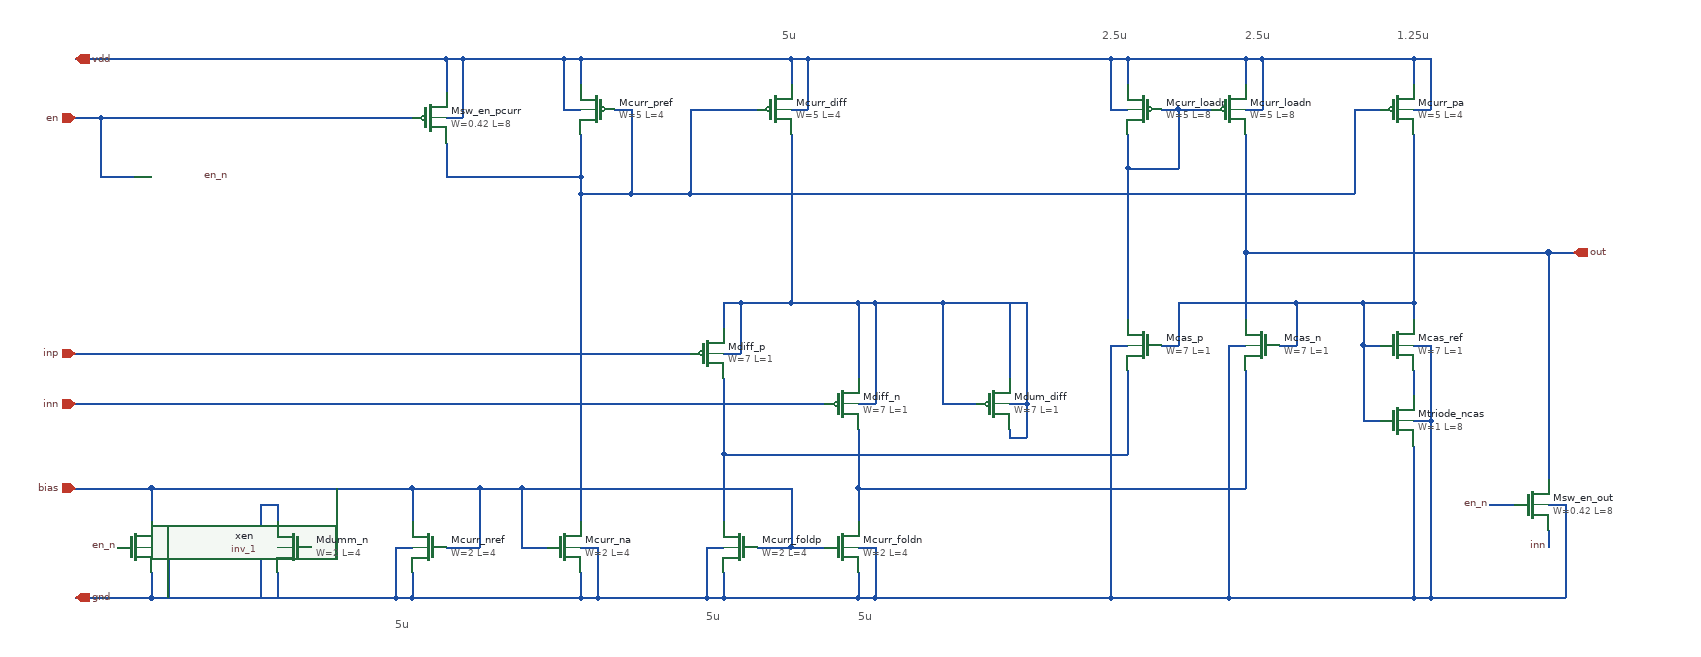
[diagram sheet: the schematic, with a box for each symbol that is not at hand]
v {xschem version=2.9.8 file_version=1.2}
G {}
K {}
V {}
S {}
E {}
T {5u} 840 -680 0 0 0.4 0.4 {}
T {5u} 750 10 0 0 0.4 0.4 {}
T {5u} 930 10 0 0 0.4 0.4 {}
T {2.5u} 1220 -680 0 0 0.4 0.4 {}
T {2.5u} 1390 -680 0 0 0.4 0.4 {}
T {5u} 380 20 0 0 0.4 0.4 {}
T {1.25u} 1570 -680 0 0 0.4 0.4 {}
N 750 -60 770 -60 {lab=gnd}
N 750 -60 750 0 {lab=gnd}
N 750 0 770 0 {lab=gnd}
N 950 -60 950 0 {lab=gnd}
N 930 -60 950 -60 {lab=gnd}
N 930 -30 930 0 {lab=gnd}
N 850 -60 890 -60 {lab=bias}
N 930 -230 950 -230 {lab=#net1}
N 950 -350 950 -230 {lab=#net1}
N 770 -350 770 -320 {lab=#net1}
N 790 -350 850 -350 {lab=#net1}
N 930 -350 930 -260 {lab=#net1}
N 850 -580 870 -580 {lab=vdd}
N 870 -640 870 -580 {lab=vdd}
N 850 -640 850 -610 {lab=vdd}
N 770 -30 770 0 {lab=gnd}
N 1370 0 1590 0 {lab=gnd}
N 1590 -180 1590 0 {lab=gnd}
N 1610 -210 1610 0 {lab=gnd}
N 930 0 950 0 {lab=gnd}
N 770 0 930 0 {lab=gnd}
N 850 -350 930 -350 {lab=#net1}
N 1590 0 1610 0 {lab=gnd}
N 850 -640 870 -640 {lab=vdd}
N 1250 -270 1250 -170 {lab=#net2}
N 1230 -300 1250 -300 {lab=gnd}
N 1230 -300 1230 0 {lab=gnd}
N 1370 -300 1390 -300 {lab=gnd}
N 1370 -300 1370 0 {lab=gnd}
N 1290 -300 1310 -300 {lab=#net3}
N 1310 -350 1310 -300 {lab=#net3}
N 1310 -350 1450 -350 {lab=#net3}
N 1450 -350 1450 -300 {lab=#net3}
N 1430 -300 1450 -300 {lab=#net3}
N 1310 -580 1350 -580 {lab=#net4}
N 1390 -410 1390 -330 {lab=out}
N 1530 -210 1550 -210 {lab=#net3}
N 1530 -300 1530 -210 {lab=#net3}
N 1530 -350 1590 -350 {lab=#net3}
N 1450 -350 1530 -350 {lab=#net3}
N 1590 -210 1610 -210 {lab=gnd}
N 1250 -640 1250 -610 {lab=vdd}
N 1230 -640 1250 -640 {lab=vdd}
N 1230 -580 1250 -580 {lab=vdd}
N 1230 -640 1230 -580 {lab=vdd}
N 1390 -580 1410 -580 {lab=vdd}
N 1410 -640 1410 -580 {lab=vdd}
N 1390 -640 1410 -640 {lab=vdd}
N 1390 -640 1390 -610 {lab=vdd}
N 580 -580 600 -580 {lab=vdd}
N 580 -640 580 -580 {lab=vdd}
N 600 -640 850 -640 {lab=vdd}
N 600 -640 600 -610 {lab=vdd}
N 380 -60 400 -60 {lab=gnd}
N 380 -60 380 0 {lab=gnd}
N 380 0 400 0 {lab=gnd}
N 620 -60 620 0 {lab=gnd}
N 600 -60 620 -60 {lab=gnd}
N 600 -30 600 0 {lab=gnd}
N 400 -30 400 0 {lab=gnd}
N 620 0 750 0 {lab=gnd}
N 600 -480 600 -90 {lab=#net5}
N 600 -480 660 -480 {lab=#net5}
N 400 -130 400 -90 {lab=bias}
N 400 -130 480 -130 {lab=bias}
N 480 -130 480 -60 {lab=bias}
N 730 -480 1520 -480 {lab=#net5}
N 1520 -580 1520 -480 {lab=#net5}
N 1520 -580 1550 -580 {lab=#net5}
N 1590 -640 1610 -640 {lab=vdd}
N 1610 -640 1610 -580 {lab=vdd}
N 1590 -580 1610 -580 {lab=vdd}
N 1590 -640 1590 -610 {lab=vdd}
N 0 -290 730 -290 {lab=inp}
N 0 -230 890 -230 {lab=inn}
N 90 -130 400 -130 {lab=bias}
N 90 0 380 0 { lab=gnd}
N 530 -130 850 -130 { lab=bias}
N 850 -130 850 -60 { lab=bias}
N 930 -350 950 -350 { lab=#net1}
N 770 -290 790 -290 { lab=#net1}
N 790 -350 790 -290 { lab=#net1}
N 810 -60 850 -60 {lab=bias}
N 770 -350 790 -350 {lab=#net1}
N 770 -260 770 -170 {lab=#net2}
N 930 -200 930 -130 {lab=#net6}
N 1230 0 1370 0 {lab=gnd}
N 1250 -640 1390 -640 {lab=vdd}
N 640 -580 660 -580 {lab=#net5}
N 440 -60 480 -60 {lab=bias}
N 600 -500 600 -480 {lab=#net5}
N 1410 -640 1590 -640 {lab=vdd}
N 850 -550 850 -350 { lab=#net1}
N 530 -60 560 -60 { lab=bias}
N 530 -130 530 -60 { lab=bias}
N 1590 -550 1590 -350 { lab=#net3}
N 1590 -300 1610 -300 { lab=gnd}
N 1610 -300 1610 -210 { lab=gnd}
N 1590 -270 1590 -240 { lab=#net7}
N 1590 -350 1590 -330 { lab=#net3}
N 1530 -300 1550 -300 { lab=#net3}
N 1530 -350 1530 -300 {lab=#net3}
N 400 0 600 0 {lab=gnd}
N 480 -130 530 -130 { lab=bias}
N 930 -130 1390 -130 { lab=#net6}
N 770 -170 1250 -170 { lab=#net2}
N 1750 -410 1780 -410 { lab=out}
N 870 -640 1230 -640 {lab=vdd}
N 1250 -510 1250 -330 { lab=#net4}
N 1390 -270 1390 -130 {lab=#net6}
N 1290 -580 1310 -580 {lab=#net4}
N 930 -130 930 -90 { lab=#net6}
N 770 -170 770 -80 { lab=#net2}
N 730 -580 810 -580 { lab=#net5}
N 730 -580 730 -480 { lab=#net5}
N 660 -580 660 -480 { lab=#net5}
N 460 -640 580 -640 {lab=vdd}
N 580 -640 600 -640 {lab=vdd}
N 600 0 620 0 {lab=gnd}
N 660 -480 730 -480 {lab=#net5}
N 950 0 1230 0 {lab=gnd}
N 440 -540 440 -500 { lab=#net5}
N 440 -640 440 -600 { lab=vdd}
N 440 -570 460 -570 { lab=vdd}
N 460 -640 460 -570 { lab=vdd}
N 440 -500 600 -500 { lab=#net5}
N 30 -570 400 -570 { lab=en}
N 90 -30 90 0 { lab=gnd}
N 90 -130 90 -90 { lab=bias}
N 30 -500 70 -500 { lab=en}
N 30 -570 30 -500 { lab=en}
N 1250 -510 1310 -510 { lab=#net4}
N 1390 -550 1390 -410 { lab=out}
N 1310 -580 1310 -510 { lab=#net4}
N 1250 -550 1250 -510 { lab=#net4}
N 0 -130 90 -130 {lab=bias}
N 0 0 90 0 { lab=gnd}
N 600 -550 600 -500 {lab=#net5}
N 0 -640 440 -640 {lab=vdd}
N 440 -640 460 -640 {lab=vdd}
N 0 -570 30 -570 { lab=en}
N 1750 -410 1750 -140 { lab=out}
N 1750 -110 1770 -110 { lab=gnd}
N 1750 -80 1750 -60 { lab=inn}
N 1390 -410 1750 -410 { lab=out}
N 1680 -110 1710 -110 { lab=en_n}
N 1770 -110 1770 0 { lab=gnd}
N 1610 0 1770 0 { lab=gnd}
N 220 -60 240 -60 {lab=gnd}
N 220 -60 220 0 {lab=gnd}
N 220 0 240 0 {lab=gnd}
N 240 -30 240 0 {lab=gnd}
N 240 -110 240 -90 { lab=gnd}
N 220 -110 240 -110 { lab=gnd}
N 220 -110 220 -60 { lab=gnd}
N 280 -60 310 -60 { lab=bias}
N 310 -130 310 -60 { lab=bias}
N 90 -60 110 -60 { lab=gnd}
N 110 -60 110 -0 { lab=gnd}
N 1110 -230 1130 -230 {lab=source}
N 1030 -230 1070 -230 { lab=source}
N 1030 -350 1030 -230 { lab=source}
N 1130 -350 1130 -230 { lab=source}
N 1030 -350 1130 -350 { lab=source}
N 1110 -200 1110 -190 { lab=source}
N 1110 -190 1130 -190 { lab=source}
N 1130 -230 1130 -190 { lab=source}
N 1110 -350 1110 -260 { lab=source}
N 950 -350 1030 -350 {}
C {ipin.sym} 0 -290 0 0 {name=p1 lab=inp}
C {ipin.sym} 0 -230 0 0 {name=p2 lab=inn}
C {ipin.sym} 0 -130 0 0 {name=p3 lab=bias}
C {opin.sym} 1780 -410 0 0 {name=p4 lab=out}
C {iopin.sym} 0 -640 0 1 {name=p5 lab=vdd}
C {iopin.sym} 0 0 0 1 {name=p6 lab=gnd}
C {sky130_fd_pr/pfet_01v8_lvt.sym} 830 -580 0 0 {name=Mcurr_diff
L=4
W=5
ad="'W * 0.29'" pd="'2 * (W + 0.29)'"
as="'W * 0.29'" ps="'2 * (W + 0.29)'"
nrd="'0.29 / W'" nrs="'0.29 / W'"
sa=0 sb=0 sd=0
nf=1 mult=8
model=pfet_01v8_lvt
spiceprefix=X
}
C {sky130_fd_pr/pfet_01v8_lvt.sym} 620 -580 0 1 {name=Mcurr_pref
L=4
W=5
ad="'W * 0.29'" pd="'2 * (W + 0.29)'"
as="'W * 0.29'" ps="'2 * (W + 0.29)'"
nrd="'0.29 / W'" nrs="'0.29 / W'"
sa=0 sb=0 sd=0
nf=1 mult=2
model=pfet_01v8_lvt
spiceprefix=X
}
C {sky130_fd_pr/nfet_01v8_lvt.sym} 420 -60 0 1 {name=Mcurr_nref
L=4
W=2
ad="'W * 0.29'" pd="'2 * (W + 0.29)'"
as="'W * 0.29'" ps="'2 * (W + 0.29)'"
nrd="'0.29 / W'" nrs="'0.29 / W'"
sa=0 sb=0 sd=0
nf=1 mult=8
model=nfet_01v8_lvt
spiceprefix=X
}
C {sky130_fd_pr/nfet_01v8_lvt.sym} 580 -60 0 0 {name=Mcurr_na
L=4
W=2
ad="'W * 0.29'" pd="'2 * (W + 0.29)'"
as="'W * 0.29'" ps="'2 * (W + 0.29)'"
nrd="'0.29 / W'" nrs="'0.29 / W'"
sa=0 sb=0 sd=0
nf=1 mult=2
model=nfet_01v8_lvt
spiceprefix=X
}
C {sky130_fd_pr/nfet_01v8_lvt.sym} 1570 -210 0 0 {name=Mtriode_ncas
L=8
W=1
ad="'W * 0.29'" pd="'2 * (W + 0.29)'"
as="'W * 0.29'" ps="'2 * (W + 0.29)'"
nrd="'0.29 / W'" nrs="'0.29 / W'"
sa=0 sb=0 sd=0
nf=1 mult=4
model=nfet_01v8_lvt
spiceprefix=X
}
C {sky130_fd_pr/pfet_01v8_lvt.sym} 1570 -580 0 0 {name=Mcurr_pa
L=4
W=5
ad="'W * 0.29'" pd="'2 * (W + 0.29)'"
as="'W * 0.29'" ps="'2 * (W + 0.29)'"
nrd="'0.29 / W'" nrs="'0.29 / W'"
sa=0 sb=0 sd=0
nf=1 mult=2
model=pfet_01v8_lvt
spiceprefix=X
}
C {sky130_fd_pr/nfet_01v8_lvt.sym} 1570 -300 0 0 {name=Mcas_ref
L=1
W=7
ad="'W * 0.29'" pd="'2 * (W + 0.29)'"
as="'W * 0.29'" ps="'2 * (W + 0.29)'"
nrd="'0.29 / W'" nrs="'0.29 / W'"
sa=0 sb=0 sd=0
nf=1 mult=8
model=nfet_01v8_lvt
spiceprefix=X
}
C {sky130_fd_pr/nfet_01v8_lvt.sym} 1410 -300 0 1 {name=Mcas_n
L=1
W=7
ad="'W * 0.29'" pd="'2 * (W + 0.29)'"
as="'W * 0.29'" ps="'2 * (W + 0.29)'"
nrd="'0.29 / W'" nrs="'0.29 / W'"
sa=0 sb=0 sd=0
nf=1 mult=8
model=nfet_01v8_lvt
spiceprefix=X
}
C {sky130_fd_pr/nfet_01v8_lvt.sym} 1270 -300 0 1 {name=Mcas_p
L=1
W=7
ad="'W * 0.29'" pd="'2 * (W + 0.29)'"
as="'W * 0.29'" ps="'2 * (W + 0.29)'"
nrd="'0.29 / W'" nrs="'0.29 / W'"
sa=0 sb=0 sd=0
nf=1 mult=8
model=nfet_01v8_lvt
spiceprefix=X
}
C {sky130_fd_pr/pfet_01v8_lvt.sym} 1270 -580 0 1 {name=Mcurr_loadp
L=8
W=5
ad="'W * 0.29'" pd="'2 * (W + 0.29)'"
as="'W * 0.29'" ps="'2 * (W + 0.29)'"
nrd="'0.29 / W'" nrs="'0.29 / W'"
sa=0 sb=0 sd=0
nf=1 mult=4
model=pfet_01v8_lvt
spiceprefix=X
}
C {sky130_fd_pr/pfet_01v8_lvt.sym} 1370 -580 0 0 {name=Mcurr_loadn
L=8
W=5
ad="'W * 0.29'" pd="'2 * (W + 0.29)'"
as="'W * 0.29'" ps="'2 * (W + 0.29)'"
nrd="'0.29 / W'" nrs="'0.29 / W'"
sa=0 sb=0 sd=0
nf=1 mult=4
model=pfet_01v8_lvt
spiceprefix=X
}
C {sky130_fd_pr/nfet_01v8_lvt.sym} 910 -60 0 0 {name=Mcurr_foldn
L=4
W=2
ad="'W * 0.29'" pd="'2 * (W + 0.29)'"
as="'W * 0.29'" ps="'2 * (W + 0.29)'"
nrd="'0.29 / W'" nrs="'0.29 / W'"
sa=0 sb=0 sd=0
nf=1 mult=8
model=nfet_01v8_lvt
spiceprefix=X
}
C {sky130_fd_pr/nfet_01v8_lvt.sym} 790 -60 0 1 {name=Mcurr_foldp
L=4
W=2
ad="'W * 0.29'" pd="'2 * (W + 0.29)'"
as="'W * 0.29'" ps="'2 * (W + 0.29)'"
nrd="'0.29 / W'" nrs="'0.29 / W'"
sa=0 sb=0 sd=0
nf=1 mult=8
model=nfet_01v8_lvt
spiceprefix=X
}
C {sky130_fd_pr/pfet_01v8_lvt.sym} 910 -230 0 0 {name=Mdiff_n
L=1
W=7
ad="'W * 0.29'" pd="'2 * (W + 0.29)'"
as="'W * 0.29'" ps="'2 * (W + 0.29)'"
nrd="'0.29 / W'" nrs="'0.29 / W'"
sa=0 sb=0 sd=0
nf=1 mult=16
model=pfet_01v8_lvt
spiceprefix=X
}
C {sky130_fd_pr/pfet_01v8_lvt.sym} 750 -290 0 0 {name=Mdiff_p
L=1
W=7
ad="'W * 0.29'" pd="'2 * (W + 0.29)'"
as="'W * 0.29'" ps="'2 * (W + 0.29)'"
nrd="'0.29 / W'" nrs="'0.29 / W'"
sa=0 sb=0 sd=0
nf=1 mult=16
model=pfet_01v8_lvt
spiceprefix=X
}
C {sky130_fd_pr/pfet_01v8_hvt.sym} 420 -570 0 0 {name=Msw_en_pcurr
L=8
W=0.42
ad="'W * 0.29'" pd="'2 * (W + 0.29)'"
as="'W * 0.29'" ps="'2 * (W + 0.29)'"
nrd="'0.29 / W'" nrs="'0.29 / W'"
sa=0 sb=0 sd=0
nf=1 mult=1
model=pfet_01v8_hvt
spiceprefix=X
}
C {ipin.sym} 0 -570 0 0 {name=p7 lab=en}
C {sky130_fd_pr/nfet_01v8.sym} 1730 -110 0 0 {name=Msw_en_out
L=8
W=0.42
ad="'W * 0.29'" pd="'2 * (W + 0.29)'"
as="'W * 0.29'" ps="'2 * (W + 0.29)'"
nrd="'0.29 / W'" nrs="'0.29 / W'"
sa=0 sb=0 sd=0
nf=1 mult=1
model=nfet_01v8
spiceprefix=X
}
C {sky130_fd_pr/nfet_01v8.sym} 70 -60 0 0 {name=Msw_en_out1
L=8
W=0.42
ad="'W * 0.29'" pd="'2 * (W + 0.29)'"
as="'W * 0.29'" ps="'2 * (W + 0.29)'"
nrd="'0.29 / W'" nrs="'0.29 / W'"
sa=0 sb=0 sd=0
nf=1 mult=1
model=nfet_01v8
spiceprefix=X
}
C {lab_wire.sym} 50 -60 2 1 {name=l4 sig_type=std_logic lab=en_n}
C {sky130_stdcells/inv_1.sym} 110 -500 0 0 {name=xen VGND=gnd VNB=gnd VPB=vdd VPWR=vdd prefix=sky130_fd_sc_hd__ }
C {lab_wire.sym} 150 -500 0 1 {name=l5 sig_type=std_logic lab=en_n}
C {lab_wire.sym} 1680 -110 2 1 {name=l1 sig_type=std_logic lab=en_n}
C {lab_wire.sym} 1750 -60 2 1 {name=l2 sig_type=std_logic lab=inn}
C {sky130_fd_pr/nfet_01v8_lvt.sym} 260 -60 0 1 {name=Mdumm_n
L=4
W=2
ad="'W * 0.29'" pd="'2 * (W + 0.29)'"
as="'W * 0.29'" ps="'2 * (W + 0.29)'"
nrd="'0.29 / W'" nrs="'0.29 / W'"
sa=0 sb=0 sd=0
nf=1 mult=4
model=nfet_01v8_lvt
spiceprefix=X
}
C {sky130_fd_pr/pfet_01v8_lvt.sym} 1090 -230 0 0 {name=Mdum_diff
L=1
W=7
ad="'W * 0.29'" pd="'2 * (W + 0.29)'"
as="'W * 0.29'" ps="'2 * (W + 0.29)'"
nrd="'0.29 / W'" nrs="'0.29 / W'"
sa=0 sb=0 sd=0
nf=1 mult=4
model=pfet_01v8_lvt
spiceprefix=X
}
